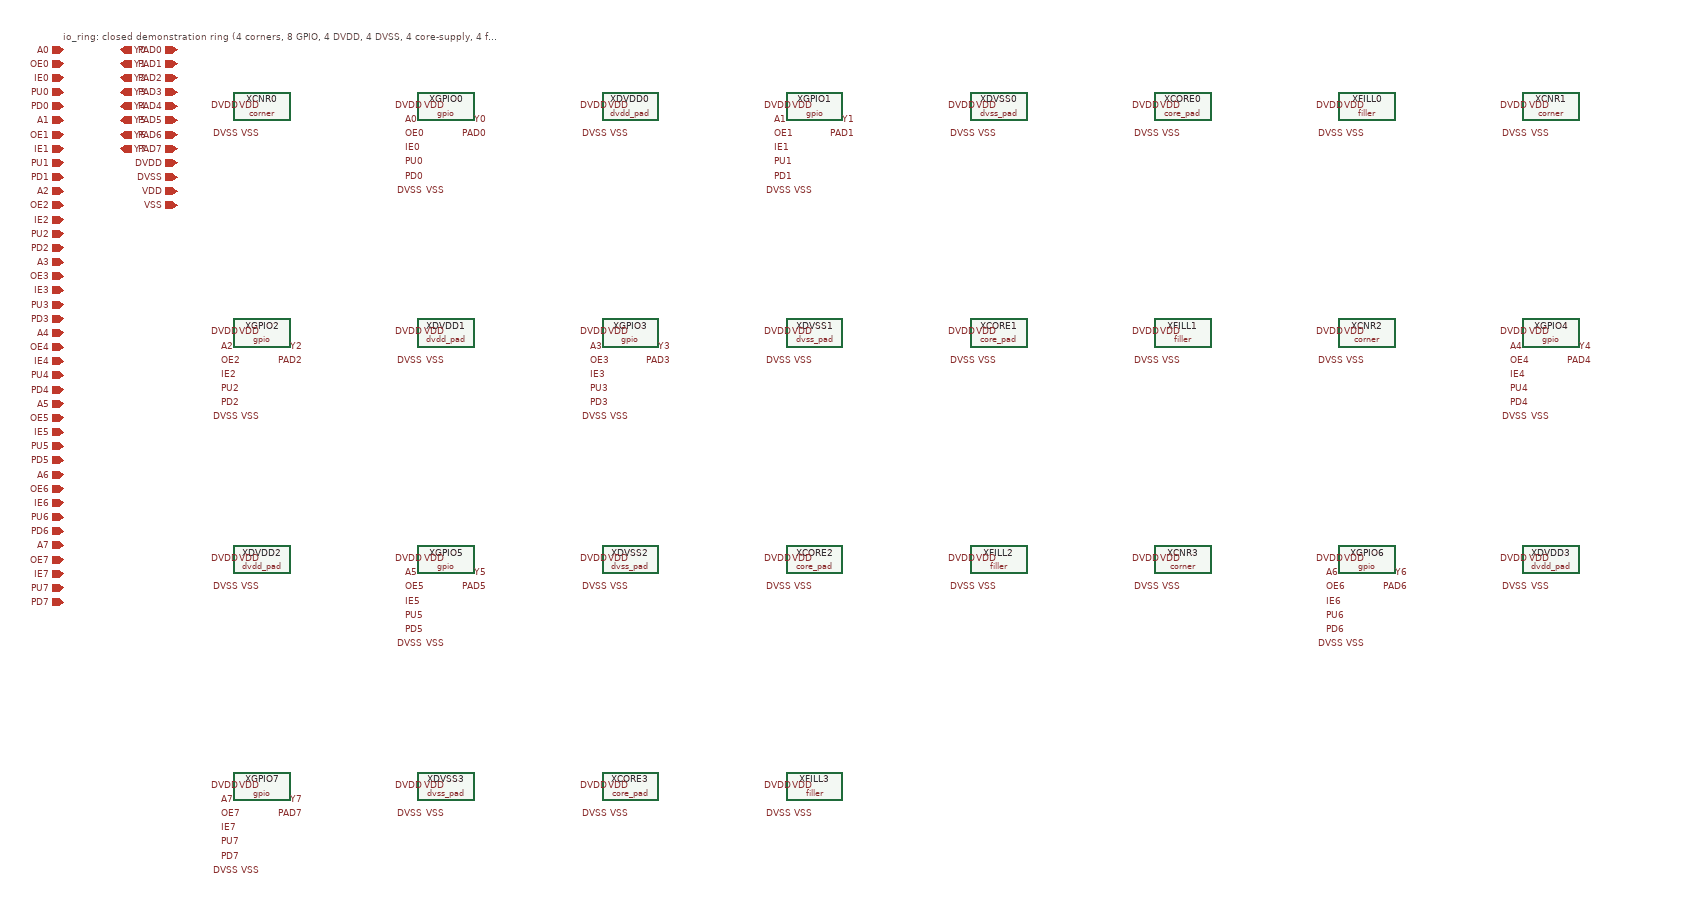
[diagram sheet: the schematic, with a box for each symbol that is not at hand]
v {xschem version=3.4.7 file_version=1.2}
G {}
K {}
V {}
S {}
E {}
C {corner.sym} 300 120 0 0 {name=XCNR0}
C {devices/lab_pin.sym} 270 120 3 0 {name=l1 sig_type=std_logic lab=DVDD}
C {devices/lab_pin.sym} 300 120 3 0 {name=l2 sig_type=std_logic lab=VDD}
C {devices/lab_pin.sym} 270 160 1 0 {name=l3 sig_type=std_logic lab=DVSS}
C {devices/lab_pin.sym} 300 160 1 0 {name=l4 sig_type=std_logic lab=VSS}
C {gpio.sym} 560 120 0 0 {name=XGPIO0}
C {devices/lab_pin.sym} 500 140 2 0 {name=l5 sig_type=std_logic lab=A0}
C {devices/lab_pin.sym} 500 160 2 0 {name=l6 sig_type=std_logic lab=OE0}
C {devices/lab_pin.sym} 500 180 2 0 {name=l7 sig_type=std_logic lab=IE0}
C {devices/lab_pin.sym} 500 200 2 0 {name=l8 sig_type=std_logic lab=PU0}
C {devices/lab_pin.sym} 500 220 2 0 {name=l9 sig_type=std_logic lab=PD0}
C {devices/lab_pin.sym} 620 140 0 0 {name=l10 sig_type=std_logic lab=Y0}
C {devices/lab_pin.sym} 620 160 0 0 {name=l11 sig_type=std_logic lab=PAD0}
C {devices/lab_pin.sym} 530 120 3 0 {name=l12 sig_type=std_logic lab=DVDD}
C {devices/lab_pin.sym} 560 120 3 0 {name=l13 sig_type=std_logic lab=VDD}
C {devices/lab_pin.sym} 530 240 1 0 {name=l14 sig_type=std_logic lab=DVSS}
C {devices/lab_pin.sym} 560 240 1 0 {name=l15 sig_type=std_logic lab=VSS}
C {dvdd_pad.sym} 820 120 0 0 {name=XDVDD0}
C {devices/lab_pin.sym} 790 120 3 0 {name=l16 sig_type=std_logic lab=DVDD}
C {devices/lab_pin.sym} 820 120 3 0 {name=l17 sig_type=std_logic lab=VDD}
C {devices/lab_pin.sym} 790 160 1 0 {name=l18 sig_type=std_logic lab=DVSS}
C {devices/lab_pin.sym} 820 160 1 0 {name=l19 sig_type=std_logic lab=VSS}
C {gpio.sym} 1080 120 0 0 {name=XGPIO1}
C {devices/lab_pin.sym} 1020 140 2 0 {name=l20 sig_type=std_logic lab=A1}
C {devices/lab_pin.sym} 1020 160 2 0 {name=l21 sig_type=std_logic lab=OE1}
C {devices/lab_pin.sym} 1020 180 2 0 {name=l22 sig_type=std_logic lab=IE1}
C {devices/lab_pin.sym} 1020 200 2 0 {name=l23 sig_type=std_logic lab=PU1}
C {devices/lab_pin.sym} 1020 220 2 0 {name=l24 sig_type=std_logic lab=PD1}
C {devices/lab_pin.sym} 1140 140 0 0 {name=l25 sig_type=std_logic lab=Y1}
C {devices/lab_pin.sym} 1140 160 0 0 {name=l26 sig_type=std_logic lab=PAD1}
C {devices/lab_pin.sym} 1050 120 3 0 {name=l27 sig_type=std_logic lab=DVDD}
C {devices/lab_pin.sym} 1080 120 3 0 {name=l28 sig_type=std_logic lab=VDD}
C {devices/lab_pin.sym} 1050 240 1 0 {name=l29 sig_type=std_logic lab=DVSS}
C {devices/lab_pin.sym} 1080 240 1 0 {name=l30 sig_type=std_logic lab=VSS}
C {dvss_pad.sym} 1340 120 0 0 {name=XDVSS0}
C {devices/lab_pin.sym} 1310 120 3 0 {name=l31 sig_type=std_logic lab=DVDD}
C {devices/lab_pin.sym} 1340 120 3 0 {name=l32 sig_type=std_logic lab=VDD}
C {devices/lab_pin.sym} 1310 160 1 0 {name=l33 sig_type=std_logic lab=DVSS}
C {devices/lab_pin.sym} 1340 160 1 0 {name=l34 sig_type=std_logic lab=VSS}
C {core_pad.sym} 1600 120 0 0 {name=XCORE0}
C {devices/lab_pin.sym} 1570 120 3 0 {name=l35 sig_type=std_logic lab=DVDD}
C {devices/lab_pin.sym} 1600 120 3 0 {name=l36 sig_type=std_logic lab=VDD}
C {devices/lab_pin.sym} 1570 160 1 0 {name=l37 sig_type=std_logic lab=DVSS}
C {devices/lab_pin.sym} 1600 160 1 0 {name=l38 sig_type=std_logic lab=VSS}
C {filler.sym} 1860 120 0 0 {name=XFILL0}
C {devices/lab_pin.sym} 1830 120 3 0 {name=l39 sig_type=std_logic lab=DVDD}
C {devices/lab_pin.sym} 1860 120 3 0 {name=l40 sig_type=std_logic lab=VDD}
C {devices/lab_pin.sym} 1830 160 1 0 {name=l41 sig_type=std_logic lab=DVSS}
C {devices/lab_pin.sym} 1860 160 1 0 {name=l42 sig_type=std_logic lab=VSS}
C {corner.sym} 2120 120 0 0 {name=XCNR1}
C {devices/lab_pin.sym} 2090 120 3 0 {name=l43 sig_type=std_logic lab=DVDD}
C {devices/lab_pin.sym} 2120 120 3 0 {name=l44 sig_type=std_logic lab=VDD}
C {devices/lab_pin.sym} 2090 160 1 0 {name=l45 sig_type=std_logic lab=DVSS}
C {devices/lab_pin.sym} 2120 160 1 0 {name=l46 sig_type=std_logic lab=VSS}
C {gpio.sym} 300 440 0 0 {name=XGPIO2}
C {devices/lab_pin.sym} 240 460 2 0 {name=l47 sig_type=std_logic lab=A2}
C {devices/lab_pin.sym} 240 480 2 0 {name=l48 sig_type=std_logic lab=OE2}
C {devices/lab_pin.sym} 240 500 2 0 {name=l49 sig_type=std_logic lab=IE2}
C {devices/lab_pin.sym} 240 520 2 0 {name=l50 sig_type=std_logic lab=PU2}
C {devices/lab_pin.sym} 240 540 2 0 {name=l51 sig_type=std_logic lab=PD2}
C {devices/lab_pin.sym} 360 460 0 0 {name=l52 sig_type=std_logic lab=Y2}
C {devices/lab_pin.sym} 360 480 0 0 {name=l53 sig_type=std_logic lab=PAD2}
C {devices/lab_pin.sym} 270 440 3 0 {name=l54 sig_type=std_logic lab=DVDD}
C {devices/lab_pin.sym} 300 440 3 0 {name=l55 sig_type=std_logic lab=VDD}
C {devices/lab_pin.sym} 270 560 1 0 {name=l56 sig_type=std_logic lab=DVSS}
C {devices/lab_pin.sym} 300 560 1 0 {name=l57 sig_type=std_logic lab=VSS}
C {dvdd_pad.sym} 560 440 0 0 {name=XDVDD1}
C {devices/lab_pin.sym} 530 440 3 0 {name=l58 sig_type=std_logic lab=DVDD}
C {devices/lab_pin.sym} 560 440 3 0 {name=l59 sig_type=std_logic lab=VDD}
C {devices/lab_pin.sym} 530 480 1 0 {name=l60 sig_type=std_logic lab=DVSS}
C {devices/lab_pin.sym} 560 480 1 0 {name=l61 sig_type=std_logic lab=VSS}
C {gpio.sym} 820 440 0 0 {name=XGPIO3}
C {devices/lab_pin.sym} 760 460 2 0 {name=l62 sig_type=std_logic lab=A3}
C {devices/lab_pin.sym} 760 480 2 0 {name=l63 sig_type=std_logic lab=OE3}
C {devices/lab_pin.sym} 760 500 2 0 {name=l64 sig_type=std_logic lab=IE3}
C {devices/lab_pin.sym} 760 520 2 0 {name=l65 sig_type=std_logic lab=PU3}
C {devices/lab_pin.sym} 760 540 2 0 {name=l66 sig_type=std_logic lab=PD3}
C {devices/lab_pin.sym} 880 460 0 0 {name=l67 sig_type=std_logic lab=Y3}
C {devices/lab_pin.sym} 880 480 0 0 {name=l68 sig_type=std_logic lab=PAD3}
C {devices/lab_pin.sym} 790 440 3 0 {name=l69 sig_type=std_logic lab=DVDD}
C {devices/lab_pin.sym} 820 440 3 0 {name=l70 sig_type=std_logic lab=VDD}
C {devices/lab_pin.sym} 790 560 1 0 {name=l71 sig_type=std_logic lab=DVSS}
C {devices/lab_pin.sym} 820 560 1 0 {name=l72 sig_type=std_logic lab=VSS}
C {dvss_pad.sym} 1080 440 0 0 {name=XDVSS1}
C {devices/lab_pin.sym} 1050 440 3 0 {name=l73 sig_type=std_logic lab=DVDD}
C {devices/lab_pin.sym} 1080 440 3 0 {name=l74 sig_type=std_logic lab=VDD}
C {devices/lab_pin.sym} 1050 480 1 0 {name=l75 sig_type=std_logic lab=DVSS}
C {devices/lab_pin.sym} 1080 480 1 0 {name=l76 sig_type=std_logic lab=VSS}
C {core_pad.sym} 1340 440 0 0 {name=XCORE1}
C {devices/lab_pin.sym} 1310 440 3 0 {name=l77 sig_type=std_logic lab=DVDD}
C {devices/lab_pin.sym} 1340 440 3 0 {name=l78 sig_type=std_logic lab=VDD}
C {devices/lab_pin.sym} 1310 480 1 0 {name=l79 sig_type=std_logic lab=DVSS}
C {devices/lab_pin.sym} 1340 480 1 0 {name=l80 sig_type=std_logic lab=VSS}
C {filler.sym} 1600 440 0 0 {name=XFILL1}
C {devices/lab_pin.sym} 1570 440 3 0 {name=l81 sig_type=std_logic lab=DVDD}
C {devices/lab_pin.sym} 1600 440 3 0 {name=l82 sig_type=std_logic lab=VDD}
C {devices/lab_pin.sym} 1570 480 1 0 {name=l83 sig_type=std_logic lab=DVSS}
C {devices/lab_pin.sym} 1600 480 1 0 {name=l84 sig_type=std_logic lab=VSS}
C {corner.sym} 1860 440 0 0 {name=XCNR2}
C {devices/lab_pin.sym} 1830 440 3 0 {name=l85 sig_type=std_logic lab=DVDD}
C {devices/lab_pin.sym} 1860 440 3 0 {name=l86 sig_type=std_logic lab=VDD}
C {devices/lab_pin.sym} 1830 480 1 0 {name=l87 sig_type=std_logic lab=DVSS}
C {devices/lab_pin.sym} 1860 480 1 0 {name=l88 sig_type=std_logic lab=VSS}
C {gpio.sym} 2120 440 0 0 {name=XGPIO4}
C {devices/lab_pin.sym} 2060 460 2 0 {name=l89 sig_type=std_logic lab=A4}
C {devices/lab_pin.sym} 2060 480 2 0 {name=l90 sig_type=std_logic lab=OE4}
C {devices/lab_pin.sym} 2060 500 2 0 {name=l91 sig_type=std_logic lab=IE4}
C {devices/lab_pin.sym} 2060 520 2 0 {name=l92 sig_type=std_logic lab=PU4}
C {devices/lab_pin.sym} 2060 540 2 0 {name=l93 sig_type=std_logic lab=PD4}
C {devices/lab_pin.sym} 2180 460 0 0 {name=l94 sig_type=std_logic lab=Y4}
C {devices/lab_pin.sym} 2180 480 0 0 {name=l95 sig_type=std_logic lab=PAD4}
C {devices/lab_pin.sym} 2090 440 3 0 {name=l96 sig_type=std_logic lab=DVDD}
C {devices/lab_pin.sym} 2120 440 3 0 {name=l97 sig_type=std_logic lab=VDD}
C {devices/lab_pin.sym} 2090 560 1 0 {name=l98 sig_type=std_logic lab=DVSS}
C {devices/lab_pin.sym} 2120 560 1 0 {name=l99 sig_type=std_logic lab=VSS}
C {dvdd_pad.sym} 300 760 0 0 {name=XDVDD2}
C {devices/lab_pin.sym} 270 760 3 0 {name=l100 sig_type=std_logic lab=DVDD}
C {devices/lab_pin.sym} 300 760 3 0 {name=l101 sig_type=std_logic lab=VDD}
C {devices/lab_pin.sym} 270 800 1 0 {name=l102 sig_type=std_logic lab=DVSS}
C {devices/lab_pin.sym} 300 800 1 0 {name=l103 sig_type=std_logic lab=VSS}
C {gpio.sym} 560 760 0 0 {name=XGPIO5}
C {devices/lab_pin.sym} 500 780 2 0 {name=l104 sig_type=std_logic lab=A5}
C {devices/lab_pin.sym} 500 800 2 0 {name=l105 sig_type=std_logic lab=OE5}
C {devices/lab_pin.sym} 500 820 2 0 {name=l106 sig_type=std_logic lab=IE5}
C {devices/lab_pin.sym} 500 840 2 0 {name=l107 sig_type=std_logic lab=PU5}
C {devices/lab_pin.sym} 500 860 2 0 {name=l108 sig_type=std_logic lab=PD5}
C {devices/lab_pin.sym} 620 780 0 0 {name=l109 sig_type=std_logic lab=Y5}
C {devices/lab_pin.sym} 620 800 0 0 {name=l110 sig_type=std_logic lab=PAD5}
C {devices/lab_pin.sym} 530 760 3 0 {name=l111 sig_type=std_logic lab=DVDD}
C {devices/lab_pin.sym} 560 760 3 0 {name=l112 sig_type=std_logic lab=VDD}
C {devices/lab_pin.sym} 530 880 1 0 {name=l113 sig_type=std_logic lab=DVSS}
C {devices/lab_pin.sym} 560 880 1 0 {name=l114 sig_type=std_logic lab=VSS}
C {dvss_pad.sym} 820 760 0 0 {name=XDVSS2}
C {devices/lab_pin.sym} 790 760 3 0 {name=l115 sig_type=std_logic lab=DVDD}
C {devices/lab_pin.sym} 820 760 3 0 {name=l116 sig_type=std_logic lab=VDD}
C {devices/lab_pin.sym} 790 800 1 0 {name=l117 sig_type=std_logic lab=DVSS}
C {devices/lab_pin.sym} 820 800 1 0 {name=l118 sig_type=std_logic lab=VSS}
C {core_pad.sym} 1080 760 0 0 {name=XCORE2}
C {devices/lab_pin.sym} 1050 760 3 0 {name=l119 sig_type=std_logic lab=DVDD}
C {devices/lab_pin.sym} 1080 760 3 0 {name=l120 sig_type=std_logic lab=VDD}
C {devices/lab_pin.sym} 1050 800 1 0 {name=l121 sig_type=std_logic lab=DVSS}
C {devices/lab_pin.sym} 1080 800 1 0 {name=l122 sig_type=std_logic lab=VSS}
C {filler.sym} 1340 760 0 0 {name=XFILL2}
C {devices/lab_pin.sym} 1310 760 3 0 {name=l123 sig_type=std_logic lab=DVDD}
C {devices/lab_pin.sym} 1340 760 3 0 {name=l124 sig_type=std_logic lab=VDD}
C {devices/lab_pin.sym} 1310 800 1 0 {name=l125 sig_type=std_logic lab=DVSS}
C {devices/lab_pin.sym} 1340 800 1 0 {name=l126 sig_type=std_logic lab=VSS}
C {corner.sym} 1600 760 0 0 {name=XCNR3}
C {devices/lab_pin.sym} 1570 760 3 0 {name=l127 sig_type=std_logic lab=DVDD}
C {devices/lab_pin.sym} 1600 760 3 0 {name=l128 sig_type=std_logic lab=VDD}
C {devices/lab_pin.sym} 1570 800 1 0 {name=l129 sig_type=std_logic lab=DVSS}
C {devices/lab_pin.sym} 1600 800 1 0 {name=l130 sig_type=std_logic lab=VSS}
C {gpio.sym} 1860 760 0 0 {name=XGPIO6}
C {devices/lab_pin.sym} 1800 780 2 0 {name=l131 sig_type=std_logic lab=A6}
C {devices/lab_pin.sym} 1800 800 2 0 {name=l132 sig_type=std_logic lab=OE6}
C {devices/lab_pin.sym} 1800 820 2 0 {name=l133 sig_type=std_logic lab=IE6}
C {devices/lab_pin.sym} 1800 840 2 0 {name=l134 sig_type=std_logic lab=PU6}
C {devices/lab_pin.sym} 1800 860 2 0 {name=l135 sig_type=std_logic lab=PD6}
C {devices/lab_pin.sym} 1920 780 0 0 {name=l136 sig_type=std_logic lab=Y6}
C {devices/lab_pin.sym} 1920 800 0 0 {name=l137 sig_type=std_logic lab=PAD6}
C {devices/lab_pin.sym} 1830 760 3 0 {name=l138 sig_type=std_logic lab=DVDD}
C {devices/lab_pin.sym} 1860 760 3 0 {name=l139 sig_type=std_logic lab=VDD}
C {devices/lab_pin.sym} 1830 880 1 0 {name=l140 sig_type=std_logic lab=DVSS}
C {devices/lab_pin.sym} 1860 880 1 0 {name=l141 sig_type=std_logic lab=VSS}
C {dvdd_pad.sym} 2120 760 0 0 {name=XDVDD3}
C {devices/lab_pin.sym} 2090 760 3 0 {name=l142 sig_type=std_logic lab=DVDD}
C {devices/lab_pin.sym} 2120 760 3 0 {name=l143 sig_type=std_logic lab=VDD}
C {devices/lab_pin.sym} 2090 800 1 0 {name=l144 sig_type=std_logic lab=DVSS}
C {devices/lab_pin.sym} 2120 800 1 0 {name=l145 sig_type=std_logic lab=VSS}
C {gpio.sym} 300 1080 0 0 {name=XGPIO7}
C {devices/lab_pin.sym} 240 1100 2 0 {name=l146 sig_type=std_logic lab=A7}
C {devices/lab_pin.sym} 240 1120 2 0 {name=l147 sig_type=std_logic lab=OE7}
C {devices/lab_pin.sym} 240 1140 2 0 {name=l148 sig_type=std_logic lab=IE7}
C {devices/lab_pin.sym} 240 1160 2 0 {name=l149 sig_type=std_logic lab=PU7}
C {devices/lab_pin.sym} 240 1180 2 0 {name=l150 sig_type=std_logic lab=PD7}
C {devices/lab_pin.sym} 360 1100 0 0 {name=l151 sig_type=std_logic lab=Y7}
C {devices/lab_pin.sym} 360 1120 0 0 {name=l152 sig_type=std_logic lab=PAD7}
C {devices/lab_pin.sym} 270 1080 3 0 {name=l153 sig_type=std_logic lab=DVDD}
C {devices/lab_pin.sym} 300 1080 3 0 {name=l154 sig_type=std_logic lab=VDD}
C {devices/lab_pin.sym} 270 1200 1 0 {name=l155 sig_type=std_logic lab=DVSS}
C {devices/lab_pin.sym} 300 1200 1 0 {name=l156 sig_type=std_logic lab=VSS}
C {dvss_pad.sym} 560 1080 0 0 {name=XDVSS3}
C {devices/lab_pin.sym} 530 1080 3 0 {name=l157 sig_type=std_logic lab=DVDD}
C {devices/lab_pin.sym} 560 1080 3 0 {name=l158 sig_type=std_logic lab=VDD}
C {devices/lab_pin.sym} 530 1120 1 0 {name=l159 sig_type=std_logic lab=DVSS}
C {devices/lab_pin.sym} 560 1120 1 0 {name=l160 sig_type=std_logic lab=VSS}
C {core_pad.sym} 820 1080 0 0 {name=XCORE3}
C {devices/lab_pin.sym} 790 1080 3 0 {name=l161 sig_type=std_logic lab=DVDD}
C {devices/lab_pin.sym} 820 1080 3 0 {name=l162 sig_type=std_logic lab=VDD}
C {devices/lab_pin.sym} 790 1120 1 0 {name=l163 sig_type=std_logic lab=DVSS}
C {devices/lab_pin.sym} 820 1120 1 0 {name=l164 sig_type=std_logic lab=VSS}
C {filler.sym} 1080 1080 0 0 {name=XFILL3}
C {devices/lab_pin.sym} 1050 1080 3 0 {name=l165 sig_type=std_logic lab=DVDD}
C {devices/lab_pin.sym} 1080 1080 3 0 {name=l166 sig_type=std_logic lab=VDD}
C {devices/lab_pin.sym} 1050 1120 1 0 {name=l167 sig_type=std_logic lab=DVSS}
C {devices/lab_pin.sym} 1080 1120 1 0 {name=l168 sig_type=std_logic lab=VSS}
C {devices/ipin.sym} 20 40 0 0 {name=p169 lab=A0}
C {devices/ipin.sym} 20 60 0 0 {name=p170 lab=OE0}
C {devices/ipin.sym} 20 80 0 0 {name=p171 lab=IE0}
C {devices/ipin.sym} 20 100 0 0 {name=p172 lab=PU0}
C {devices/ipin.sym} 20 120 0 0 {name=p173 lab=PD0}
C {devices/ipin.sym} 20 140 0 0 {name=p174 lab=A1}
C {devices/ipin.sym} 20 160 0 0 {name=p175 lab=OE1}
C {devices/ipin.sym} 20 180 0 0 {name=p176 lab=IE1}
C {devices/ipin.sym} 20 200 0 0 {name=p177 lab=PU1}
C {devices/ipin.sym} 20 220 0 0 {name=p178 lab=PD1}
C {devices/ipin.sym} 20 240 0 0 {name=p179 lab=A2}
C {devices/ipin.sym} 20 260 0 0 {name=p180 lab=OE2}
C {devices/ipin.sym} 20 280 0 0 {name=p181 lab=IE2}
C {devices/ipin.sym} 20 300 0 0 {name=p182 lab=PU2}
C {devices/ipin.sym} 20 320 0 0 {name=p183 lab=PD2}
C {devices/ipin.sym} 20 340 0 0 {name=p184 lab=A3}
C {devices/ipin.sym} 20 360 0 0 {name=p185 lab=OE3}
C {devices/ipin.sym} 20 380 0 0 {name=p186 lab=IE3}
C {devices/ipin.sym} 20 400 0 0 {name=p187 lab=PU3}
C {devices/ipin.sym} 20 420 0 0 {name=p188 lab=PD3}
C {devices/ipin.sym} 20 440 0 0 {name=p189 lab=A4}
C {devices/ipin.sym} 20 460 0 0 {name=p190 lab=OE4}
C {devices/ipin.sym} 20 480 0 0 {name=p191 lab=IE4}
C {devices/ipin.sym} 20 500 0 0 {name=p192 lab=PU4}
C {devices/ipin.sym} 20 520 0 0 {name=p193 lab=PD4}
C {devices/ipin.sym} 20 540 0 0 {name=p194 lab=A5}
C {devices/ipin.sym} 20 560 0 0 {name=p195 lab=OE5}
C {devices/ipin.sym} 20 580 0 0 {name=p196 lab=IE5}
C {devices/ipin.sym} 20 600 0 0 {name=p197 lab=PU5}
C {devices/ipin.sym} 20 620 0 0 {name=p198 lab=PD5}
C {devices/ipin.sym} 20 640 0 0 {name=p199 lab=A6}
C {devices/ipin.sym} 20 660 0 0 {name=p200 lab=OE6}
C {devices/ipin.sym} 20 680 0 0 {name=p201 lab=IE6}
C {devices/ipin.sym} 20 700 0 0 {name=p202 lab=PU6}
C {devices/ipin.sym} 20 720 0 0 {name=p203 lab=PD6}
C {devices/ipin.sym} 20 740 0 0 {name=p204 lab=A7}
C {devices/ipin.sym} 20 760 0 0 {name=p205 lab=OE7}
C {devices/ipin.sym} 20 780 0 0 {name=p206 lab=IE7}
C {devices/ipin.sym} 20 800 0 0 {name=p207 lab=PU7}
C {devices/ipin.sym} 20 820 0 0 {name=p208 lab=PD7}
C {devices/opin.sym} 100 40 0 0 {name=p209 lab=Y0}
C {devices/opin.sym} 100 60 0 0 {name=p210 lab=Y1}
C {devices/opin.sym} 100 80 0 0 {name=p211 lab=Y2}
C {devices/opin.sym} 100 100 0 0 {name=p212 lab=Y3}
C {devices/opin.sym} 100 120 0 0 {name=p213 lab=Y4}
C {devices/opin.sym} 100 140 0 0 {name=p214 lab=Y5}
C {devices/opin.sym} 100 160 0 0 {name=p215 lab=Y6}
C {devices/opin.sym} 100 180 0 0 {name=p216 lab=Y7}
C {devices/iopin.sym} 180 40 0 0 {name=p217 lab=PAD0}
C {devices/iopin.sym} 180 60 0 0 {name=p218 lab=PAD1}
C {devices/iopin.sym} 180 80 0 0 {name=p219 lab=PAD2}
C {devices/iopin.sym} 180 100 0 0 {name=p220 lab=PAD3}
C {devices/iopin.sym} 180 120 0 0 {name=p221 lab=PAD4}
C {devices/iopin.sym} 180 140 0 0 {name=p222 lab=PAD5}
C {devices/iopin.sym} 180 160 0 0 {name=p223 lab=PAD6}
C {devices/iopin.sym} 180 180 0 0 {name=p224 lab=PAD7}
C {devices/iopin.sym} 180 200 0 0 {name=p225 lab=DVDD}
C {devices/iopin.sym} 180 220 0 0 {name=p226 lab=DVSS}
C {devices/iopin.sym} 180 240 0 0 {name=p227 lab=VDD}
C {devices/iopin.sym} 180 260 0 0 {name=p228 lab=VSS}
T {io_ring: closed demonstration ring (4 corners, 8 GPIO, 4 DVDD, 4 DVSS, 4 core-supply, 4 filler) around an empty core.} 20 10 0 0 0.4 0.4 {}
